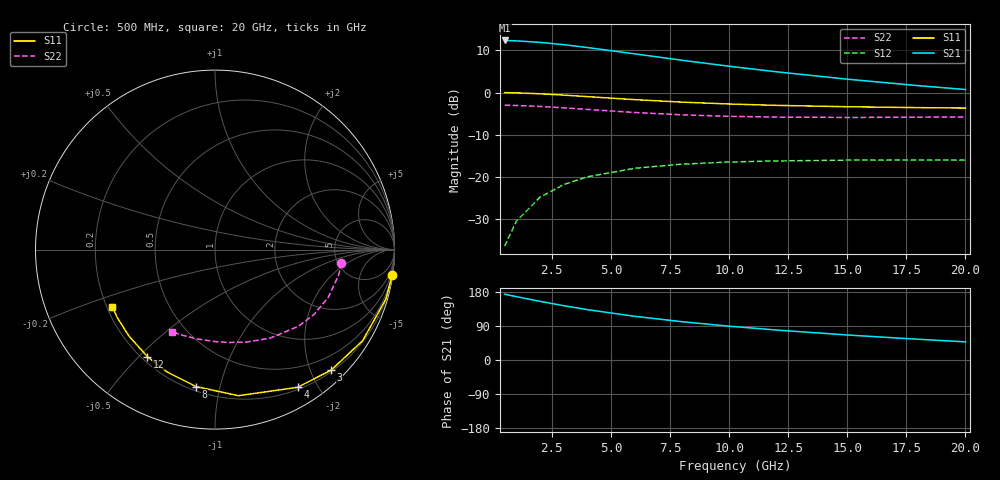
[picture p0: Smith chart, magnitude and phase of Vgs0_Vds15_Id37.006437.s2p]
# Hz S RI R 50
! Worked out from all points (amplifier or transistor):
!   12 points, 500 MHz to 20 GHz, reference 50 ohm
!   highest |S21| = 12.3 dB at 500 MHz (marker M1)
!   |S21| within 3 dB of that: start of sweep to 5.784 GHz
!   unconditionally stable (mu >= 1): 18.7 GHz to end of sweep
!   at 2 GHz: K = 0.10, MSG = 18.3 dB, |S12| = -24.7 dB
!   at 8 GHz: K = 0.40, MSG = 12.3 dB, |S12| = -16.9 dB
!   at 20 GHz: K = 1.08, MAG = 6.6 dB, |S12| = -16.0 dB
!   S11 on the Smith chart (normalised r, x): 500 MHz: 0, -14; 3 GHz: 0.23, -2.34; 4 GHz: 0.23, -1.74; 8 GHz: 0.23, -0.84; 12 GHz: 0.22, -0.53; 20 GHz: 0.22, -0.25
5e8  0.9877 -0.1409  -4.1 0.4652  0.00147 0.0152  0.7046 -0.0726
1e9  0.952 -0.2756  -3.979 0.9096  0.00576 0.0297  0.6887 -0.1425
2e9  0.8229 -0.5072  -3.542 1.669  0.0212 0.054  0.6311 -0.2663
3e9  0.6476 -0.671  -2.95 2.196  0.0421 0.07  0.552 -0.361
4e9  0.4604 -0.7673  -2.321 2.492  0.0641 0.0778  0.4658 -0.4266
6e9  0.1306 -0.8139  -1.228 2.591  0.1021 0.076  0.3067 -0.4935
8e9  -0.1068 -0.7629  -0.4638 2.363  0.1279 0.0627  0.18 -0.5147
1e10  -0.2673 -0.6815  0.0264 2.045  0.1436 0.0465  0.0805 -0.5174
1.2e10  -0.3762 -0.5967  0.333 1.727  0.1526 0.0307  -0.00107 -0.5123
1.5e10  -0.4807 -0.4801  0.5853 1.314  0.1584 0.00978  -0.1031 -0.4973
1.8e10  -0.544 -0.3794  0.6968 0.9844  0.159 -0.00738  -0.1893 -0.475
2e10  -0.5722 -0.3199  0.7273 0.8058  0.158 -0.017  -0.2403 -0.4563
